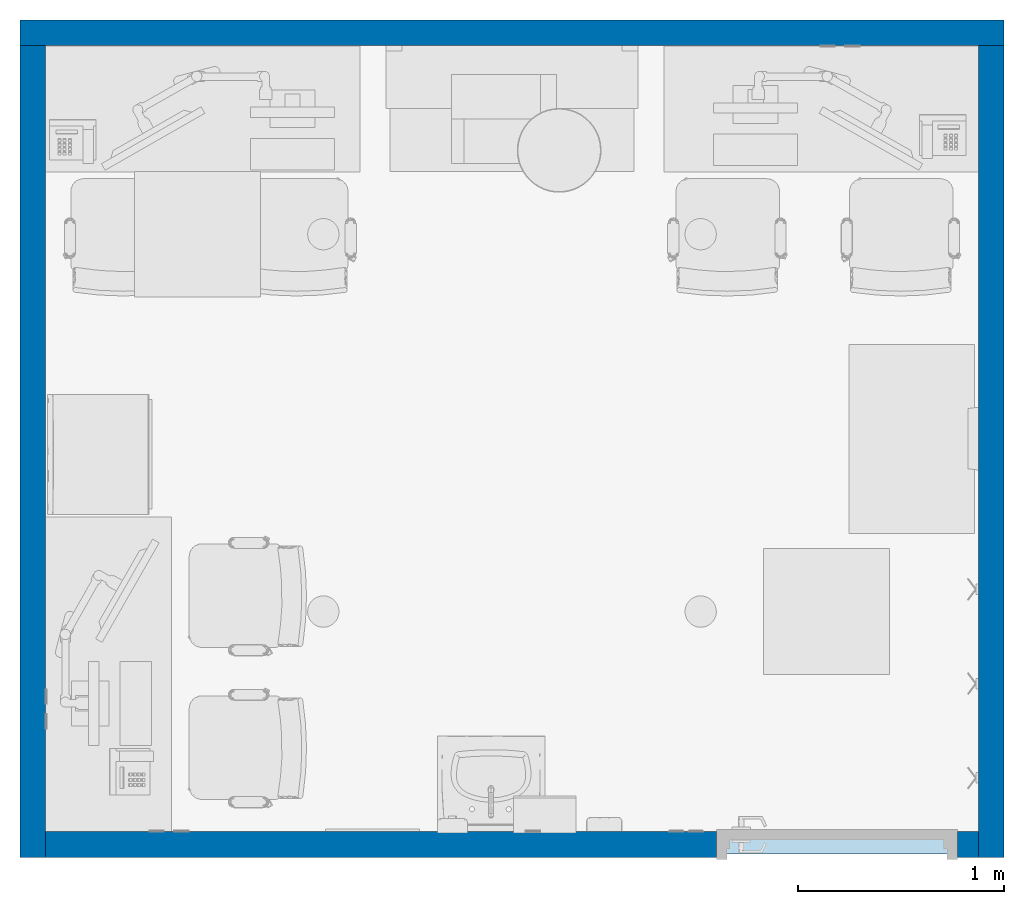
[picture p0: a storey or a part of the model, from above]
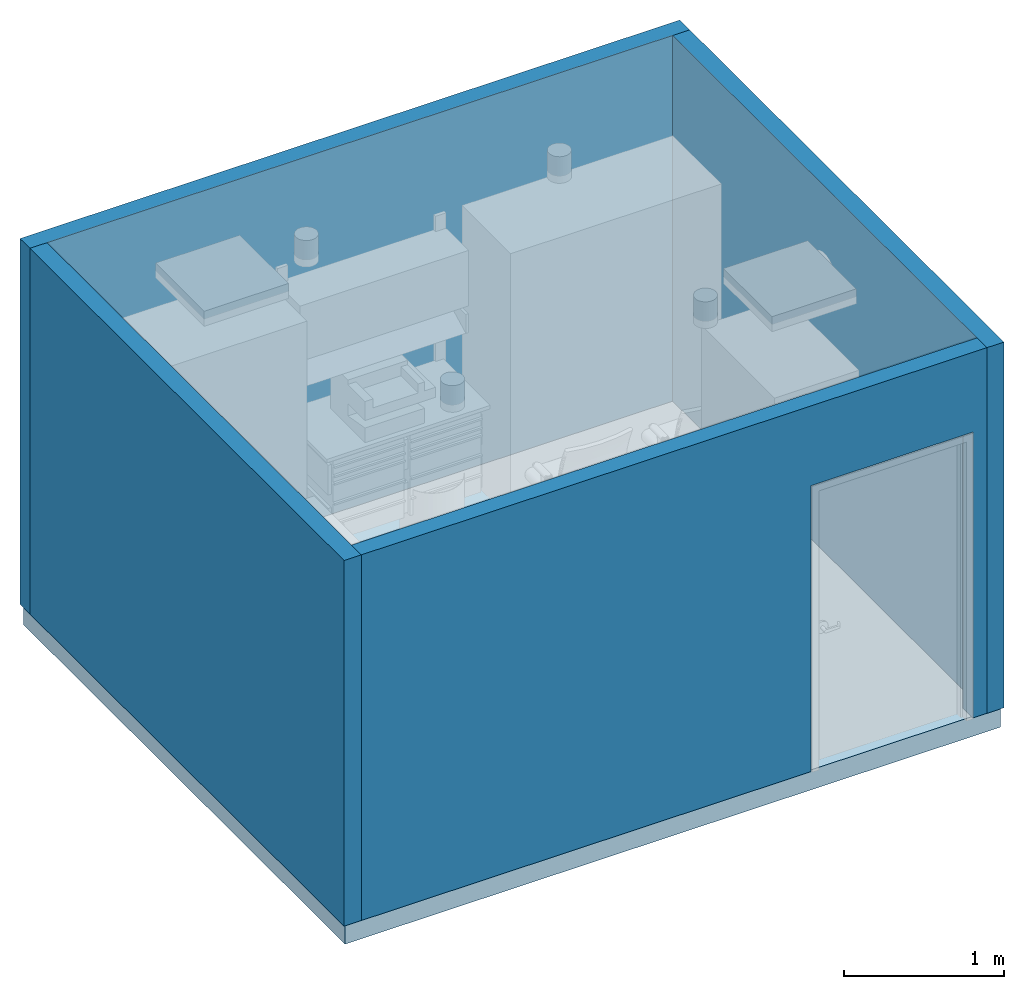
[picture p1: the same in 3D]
Properties of the parts of a building model (IFC2X3)

# File
Description: ViewDefinition [CoordinationView_V2.0]
File name: (ROOM CODE)
Time: 2018-06-28T13:35:36
Written by: The EXPRESS Data Manager Version 5.02.0100.07 : 28 Aug 2013
Made in: 20170223_1515(x64) - Exporter 18.0.0.420 - Alternate UI 18.0.0.420
Comment: STEP Physical File produced by: The EXPRESS Data Manager Version 5.02.0100.07 : 28 Aug 2013 * Module: EDMstepFileFactory/EDMstandAlone * Creation date: Thu Jun 28 13:35:36 2018 * Host: L105-OKC * Database: C:\Users\jet\AppData\Local\Temp\{82482667-5074-4ABC-837D-4FFCA593AA33}\ifc * Database version: 5507 * Database creation date: Thu Jun 28 13:35:34 2018 * Schema: IFC2X3 * Model: DataRepository.ifc * Model creation date: Thu Jun 28 13:35:35 2018 * Header model: DataRepository.ifc_HeaderModel * Header model creation date: Thu Jun 28 13:35:35 2018 * EDMuser: sdai-user * EDMgroup: sdai-group * License ID and type: 5605 : Permanent license. Expiry date: * EDMstepFileFactory options: 020000

# IfcProject, (ROOM CODE)
LongName: ROOM NAME & AREA; Phase: DRAFT

# IfcSite, Default
RefLatitude: 42, 21, 31, 181945; RefLongitude: -71, -3, -24, -263305; RefElevation: 0 ft

# IfcBuilding, EYE CLINIC: OPTHALMOLOGY AND OPTOMETRY SERVICES (Ch. 233)
LongName: EYE CLINIC: OPTHALMOLOGY AND OPTOMETRY SERVICES (Ch. 233)
Pset_BuildingCommon - NumberOfStoreys: 1

# IfcBuildingStorey, DATUM
In: EYE CLINIC: OPTHALMOLOGY AND OPTOMETRY SERVICES (Ch. 233)
LongName: DATUM; Elevation: 0 ft

# IfcSpace, (OPLV2)
In: DATUM
LongName: LOW VISION EXAM ROOM, OPTOMETRY; InteriorOrExteriorSpace: INTERNAL
Pset_SpaceCommon - Reference: LOW VISION EXAM ROOM, OPTOMETRY (OPLV2); Category: Rooms; CeilingCovering: AT1; WallCovering: GPT; FloorCovering: UT

# IfcBuildingElementProxy: 24" x 24", Supply Diffuser:24" x 24":983307
In: (OPLV2)
Type - Classification: D3040100 Air Distribution Systems (Uniformat)
Pset_BuildingElementProxyCommon - Reference: 24" x 24"

# IfcBuildingElementProxy: 24" x 24", Return Register:24" x 24":983515
In: (OPLV2)
Type - Classification: D3040200 Exhaust Ventilation Systems (Uniformat)
Pset_BuildingElementProxyCommon - Reference: 24" x 24"

# IfcBuildingElementProxy: A1066 - Mirror, Float Glass, A1066 - Mirror, Float Glass:A1066 - Mirror, Float Glass:2112246
In: (OPLV2)
Type - Classification: CC (Uniformat); Material: mirror glass, Stainless Steel
Pset_BuildingElementProxyCommon - Reference: A1066 - Mirror, Float Glass

# IfcBuildingElementProxy: A5075 - Dispenser, Soap, A5075 - Dispenser, Soap:A5075 - Dispenser, Soap:2112275
In: (OPLV2)
Type - Classification: VV (Uniformat)
Pset_BuildingElementProxyCommon - Reference: A5075 - Dispenser, Soap

# IfcBuildingElementProxy: A5077 - Dispenser, Hand Sanitizer, Hands free, A5077 - Dispenser, Hand Sanitizer, Hands free:A5077 - Dispenser, Hand Sanitizer, Hands free:2112245
In: (OPLV2)
Type - Classification: VV (Uniformat); Material: White Paint, Glass
Pset_BuildingElementProxyCommon - Reference: A5077 - Dispenser, Hand Sanitizer, Hands free

# IfcBuildingElementProxy: A5082 - Dispenser, Paper Towel, Sensor, Hands Free, A5082 - Dispenser, Paper Towel, Sensor, Hands Free:A5082 - Dispenser, Paper Towel, Sensor, Hands Free:2112247
In: (OPLV2)
Type - Classification: CC (Uniformat)
Pset_BuildingElementProxyCommon - Reference: A5082 - Dispenser, Paper Towel, Sensor, Hands Free

# IfcBuildingElementProxy: A5145 - Hook, Garment, Double (3)
In: (OPLV2)
Type - Classification: CC (Uniformat)
Pset_BuildingElementProxyCommon - Reference: A5145 - Hook, Garment, Double
Name (A5145 - Hook, Garment, Double:A5145 - Hook, Garment, Double:...)
2112291
2112328
2112329

# IfcBuildingElementProxy: A5225 - Dual Flat Panel Monitor ARMS (3)
In: (OPLV2)
Type - Classification: VV (Uniformat)
Pset_BuildingElementProxyCommon - Reference: A5225 - Dual Flat Panel Monitor ARMS
Name (A5225 - Dual Monitor Arms:A5225 - Dual Flat Panel Monitor ARMS:...)
2112259
2112262
2112311

# IfcBuildingElementProxy: Duplex (4)
In: (OPLV2)
Pset_BuildingElementProxyCommon - Reference: Duplex
Name (Outlet, Duplex, Wall:Duplex:...)
2460634
2461034
2461155
2461191

# IfcBuildingElementProxy: E0212 - Worksurface, with Overhd Cab & Drwrs, Wall Mtd, 48 W (1), E0212 - Worksurface, with Overhd Cab & Drwrs, Wall Mtd, 48 W:E0212 - Worksurface, with Overhd Cab & Drwrs, Wall Mtd, 48 W (1):2112248
In: (OPLV2)
Type - Classification: VV (Uniformat); Material: Wall Material (1)
Pset_BuildingElementProxyCommon - Reference: E0212 - Worksurface, with Overhd Cab & Drwrs, Wall Mtd, 48 W (1)

# IfcBuildingElementProxy: E0214 - Worksurface, with Overhead Cab, Wall Mtd, 60 W (1) (3)
In: (OPLV2)
Type - Material: EquipSpace
Pset_BuildingElementProxyCommon - Reference: E0214 - Worksurface, with Overhead Cab, Wall Mtd, 60 W (1)
Name (E0214 - Worksurface, with Overhead Cab, Wall Mtd, 60 W:E0214 - Worksurface, with Overhead Cab, Wall Mtd, 60 W (1):...)
2112249
2112256
2112307

# IfcBuildingElementProxy: E0820 - Module, Storage, 2-Drw Lateral File & Bookcase 24 D x 36 W x 66 H, E0820 - Module, Storage, 2-Drw Lateral File & Bookcase 24 D x 36 W x 66 H:E0820 - Module, Storage, 2-Drw Lateral File & Bookcase 24 D x 36 W x 66 H:2168803
In: (OPLV2)
Type - Classification: VV (Uniformat)
Pset_BuildingElementProxyCommon - Reference: E0820 - Module, Storage, 2-Drw Lateral File & Bookcase 24 D x 36 W x 66 H

# IfcBuildingElementProxy: E0906 - Locker, Supply, General, Wall Mtd, 23W x 20D, E0906 - Locker, Supply, General, Wall Mtd, 23W x 20D:E0906 - Locker, Supply, General, Wall Mtd, 23W x 20D:2112250
In: (OPLV2)
Type - Classification: VV (Uniformat)
Pset_BuildingElementProxyCommon - Reference: E0906 - Locker, Supply, General, Wall Mtd, 23W x 20D

# IfcBuildingElementProxy: F0300 - Chair, Task, Swivel, With Arms (6)
In: (OPLV2)
Type - Classification: VV (Uniformat)
Pset_BuildingElementProxyCommon - Reference: F0300 - Chair, Task, Swivel, With Arms
Name (F0300 - Chair, Task, Swivel, With Arms:F0300 - Chair, Task, Swivel, With Arms:...)
2112251
2112252
2112253
2112257
2112308
2112309

# IfcBuildingElementProxy: F2000 - Basket, Wastepaper 16"x 16", F2000 - Basket, Wastepaper, Fire Resistant:F2000 - Basket, Wastepaper 16"x 16":2112244
In: (OPLV2)
Type - Classification: VV (Uniformat)
Pset_BuildingElementProxyCommon - Reference: F2000 - Basket, Wastepaper 16"x 16"

# IfcBuildingElementProxy: F3200 - Clock, Battery, 12in Dia, F3200 - Clock, Battery, 12in Dia:F3200 - Clock, Battery, 12in Dia:2112304
In: (OPLV2)
Type - Classification: VV (Uniformat); Material: WHITE
Pset_BuildingElementProxyCommon - Reference: F3200 - Clock, Battery, 12in Dia

# IfcBuildingElementProxy: M1800 - Computer with Double Flat Panel Monitors (3)
In: (OPLV2)
Type - Classification: VV (Uniformat)
Pset_BuildingElementProxyCommon - Reference: M1800 - Computer with Double Flat Panel Monitors
Name (M1800 - Monitor, Computer:M1800 - Computer with Double Flat Panel Monitors:...)
2112260
2112263
2112312

# IfcBuildingElementProxy: M1801 Computer (3)
In: (OPLV2)
Type - Classification: VV (Uniformat)
Pset_BuildingElementProxyCommon - Reference: M1801 Computer
Name (M1801 - Computer, Microprocessing, With Flat Panel Monitor:M1801 Computer:...)
2112258
2112261
2112310

# IfcBuildingElementProxy: M1825 - Printer, Computer, M1825 - Printer, Computer:M1825 - Printer, Computer:2112254
In: (OPLV2)
Type - Classification: VV (Uniformat)
Pset_BuildingElementProxyCommon - Reference: M1825 - Printer, Computer

# IfcBuildingElementProxy: P3200 - Lavatory, Viteous China, Slab Type WSens Op Fauc, P3200 - Lavatory, Vitreous China, Slab Type WSens Op Fauc:P3200 - Lavatory, Viteous China, Slab Type WSens Op Fauc:2112255
In: (OPLV2)
Type - Classification: CC (Uniformat); Material: Vitreous China, Metal - Steel, Polished
Pset_BuildingElementProxyCommon - Reference: P3200 - Lavatory, Viteous China, Slab Type WSens Op Fauc

# IfcBuildingElementProxy: Single (2)
In: (OPLV2)
Type - Material: Plastic - White
Pset_BuildingElementProxyCommon - Reference: Single
Name (Switch-Single:Single:...)
2112295
2112296

# IfcBuildingElementProxy: Telephone/Data (3)
In: (OPLV2)
Pset_BuildingElementProxyCommon - Reference: Telephone/Data
Name (Outlet, Communications:Telephone/Data:...)
2460657
2461035
2461192

# IfcBuildingElementProxy: UXX15 - Telephone, Desk, Low Vision (3)
In: (OPLV2)
Type - Classification: VV (Uniformat); Material: Plastic - White, Plastic - Gray,Dark
Pset_BuildingElementProxyCommon - Reference: UXX15 - Telephone, Desk, Low Vision
Name (UXX15 - Telephone, Desk, Low Vision:UXX15 - Telephone, Desk, Low Vision:...)
2112287
2112317
2112321

# IfcCovering: Compound Ceiling:2' x 2' ACT System, Compound Ceiling:2' x 2' ACT System:962850
In: (OPLV2)
PredefinedType: CEILING; Classification: C3030210 Suspended Ceilings - Acoustical (Uniformat); Material: Default 0.135417 ft, Acoustic Ceiling Tile 24 x 24 0.0520833 ft
Pset_CoveringCommon - Reference: 2' x 2' ACT System; Finish: Acoustic Ceiling Tile 24 x 24;; TotalThickness: 0.1875 ft

# IfcDoor: 42" x 84", Single - Flush:42" x 84":2319567
In: DATUM
Type - ParameterTakesPrecedence: no; Sizeable: no; Classification: C1020 Interior Doors (Uniformat); Material: Door - Hardware, Door - Wood Panel, Door - H.M. Frame
OverallHeight: 7.16667 ft; OverallWidth: 3.83333 ft
Pset_DoorCommon - IsExternal: no; Reference: 42" x 84"

# IfcFlowTerminal: 6" (4)
In: (OPLV2)
Type - Classification: D5020220 Lighting - Incandescent (Uniformat)
Pset_DistributionFlowElementCommon - Reference: 6"
Name (Downlight - Recessed Can:6":...)
2303947
2461883
2461925
2461926

# IfcSlab: Floor:Generic - 6", Floor:Generic - 6":961598
In: DATUM
PredefinedType: FLOOR; Classification: B1010 Floor Construction (Uniformat); Material: Default Floor 0.5 ft
Pset_SlabCommon - Reference: Generic - 6"; IsExternal: no; LoadBearing: no; PitchAngle: 0 deg

# IfcWallStandardCase: Basic Wall:Interior - 4 7/8" (4)
In: DATUM
Type - PredefinedType: STANDARD; Material: Default Wall 0.40625 ft
Classification: B2010 Exterior Walls (Uniformat)
Pset_WallCommon - LoadBearing: no; Reference: Interior - 4 7/8"; ExtendToStructure: no; IsExternal: yes
Name (Basic Wall:Interior - 4 7/8":...)
1978650
1978715
1980990
1981561
